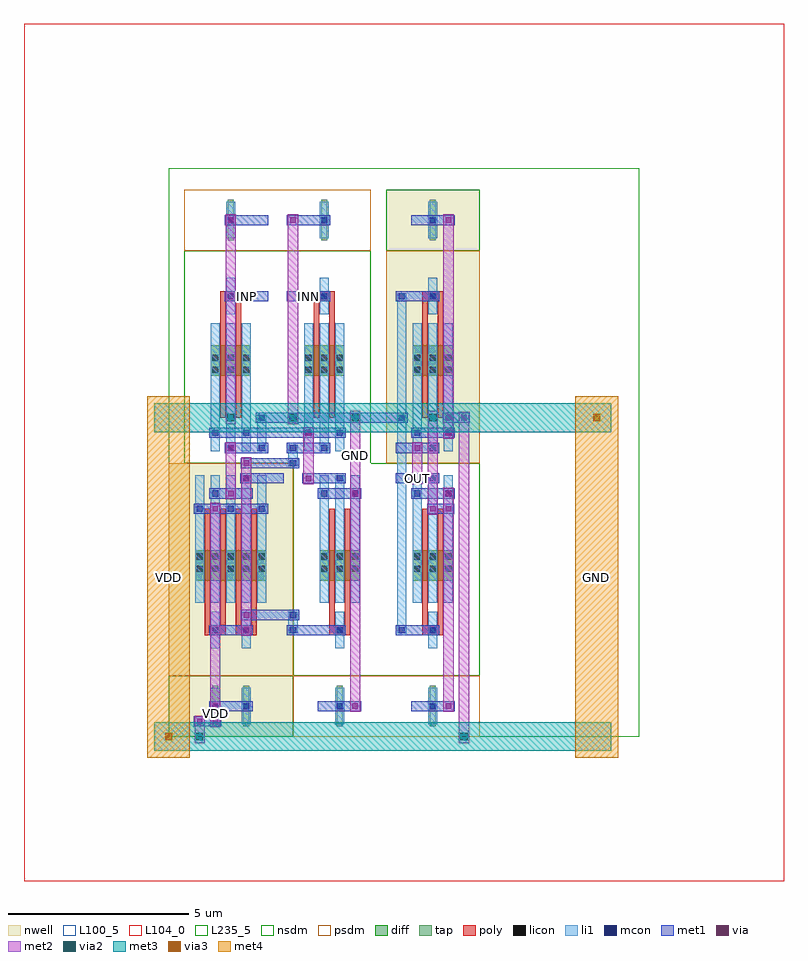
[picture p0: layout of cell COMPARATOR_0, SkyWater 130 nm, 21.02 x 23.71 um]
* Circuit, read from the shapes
.subckt COMPARATOR_0 GND INN INP OUT VDD
XM1 n1 INP n2 GND sky130_fd_pr__nfet_01v8 w=0.84 l=0.15 m=2
XM2 n3 INN n2 GND sky130_fd_pr__nfet_01v8 w=0.84 l=0.15 m=2
XM3 n2 n3 GND GND sky130_fd_pr__nfet_01v8 w=0.84 l=0.15 m=2
XM4 OUT n1 GND GND sky130_fd_pr__nfet_01v8 w=0.84 l=0.15 m=2
XM5 n1 n3 VDD VDD sky130_fd_pr__pfet_01v8 w=0.84 l=0.15 m=2
XM6 n3 n3 VDD VDD sky130_fd_pr__pfet_01v8 w=0.84 l=0.15 m=2
XM7 OUT n1 VDD VDD sky130_fd_pr__pfet_01v8 w=0.84 l=0.15 m=2
.ends

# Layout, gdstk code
from math import pi, radians
import gdstk
lib = gdstk.Library(unit=1e-6, precision=1e-09)
def R(c, l, rs):  # rectangles x0, y0, x1, y1
    for r in rs: c.add(gdstk.rectangle(r[:2], r[2:], *l))
def A(c, l, x, y, w, h, nx, ny, dx, dy):  # array of equal rectangles
    R(c, l, [(x+i*dx, y+j*dy, x+i*dx+w, y+j*dy+h) for i in range(nx) for j in range(ny)])
def P(c, l, *ps):  # polygons
    for p in ps: c.add(gdstk.Polygon(p, *l))
nwell = (64, 20)
diff = (65, 20)
tap = (65, 44)
poly = (66, 20)
licon = (66, 44)
li1 = (67, 20)
mcon = (67, 44)
met1 = (68, 20)
via = (68, 44)
met2 = (69, 20)
via2 = (69, 44)
met3 = (70, 20)
via3 = (70, 44)
met4 = (71, 20)
nsdm = (93, 44)
psdm = (94, 20)
L100_5 = (100, 5)
L104_0 = (104, 0)
L235_5 = (235, 5)

scm_pmos_73046675_x1_y1_ = lib.new_cell('SCM_PMOS_73046675_X1_Y1_1678552163')
R(scm_pmos_73046675_x1_y1_, nwell, [(0,0,3.44,7.56)])
R(scm_pmos_73046675_x1_y1_, diff, [(0.735,2.415,2.705,3.255)])
R(scm_pmos_73046675_x1_y1_, tap, [(1.205,6.16,1.375,7.28), (2.065,6.16,2.235,7.28)])
A(scm_pmos_73046675_x1_y1_, poly, 1, 1.26, 0.15, 3.36, 4, 1, 0.43, 0)
R(scm_pmos_73046675_x1_y1_, poly, [(1,4.485,1.58,4.755), (1.86,4.485,2.44,4.755)])
A(scm_pmos_73046675_x1_y1_, licon, 0.775, 2.495, 0.17, 0.17, 3, 2, 0.43, 0.34)
A(scm_pmos_73046675_x1_y1_, licon, 1.635, 2.495, 0.17, 0.17, 3, 2, 0.43, 0.34)
R(scm_pmos_73046675_x1_y1_, licon, [(1.205,4.535,1.375,4.705), (2.065,4.535,2.235,4.705), (1.205,6.635,1.375,6.805), (2.065,6.635,2.235,6.805)])
A(scm_pmos_73046675_x1_y1_, li1, 0.735, 0.335, 0.25, 3.53, 5, 1, 0.43, 0)
R(scm_pmos_73046675_x1_y1_, li1, [(1.165,4.115,1.415,5.125), (2.025,4.115,2.275,5.125), (1.165,6.215,1.415,7.225), (2.025,6.215,2.275,7.225)])
A(scm_pmos_73046675_x1_y1_, mcon, 0.775, 1.175, 0.17, 0.17, 3, 1, 0.86, 0)
R(scm_pmos_73046675_x1_y1_, mcon, [(1.205,0.335,1.375,0.505), (2.065,0.755,2.235,0.925), (1.205,4.535,1.375,4.705), (2.065,4.535,2.235,4.705), (1.205,6.635,1.375,6.805), (2.065,6.635,2.235,6.805)])
R(scm_pmos_73046675_x1_y1_, met1, [(0.26,0.28,1.46,0.56), (1.12,0.7,2.32,0.98), (0.69,1.12,2.75,1.4), (1.12,4.48,2.32,4.76), (1.12,6.58,2.32,6.86)])
R(scm_pmos_73046675_x1_y1_, via, [(1.215,0.345,1.365,0.495), (2.075,1.185,2.225,1.335), (1.215,4.545,1.365,4.695), (2.075,6.645,2.225,6.795)])
R(scm_pmos_73046675_x1_y1_, met2, [(1.15,0.26,1.43,4.78), (2.01,1.1,2.29,6.88)])
R(scm_pmos_73046675_x1_y1_, nsdm, [(0,5.88,3.44,7.56)])
R(scm_pmos_73046675_x1_y1_, psdm, [(0,0,3.44,5.88)])
R(scm_pmos_73046675_x1_y1_, L100_5, [(0,0,3.44,7.56)])

nmos_s_25628869_x1_y1_16 = lib.new_cell('NMOS_S_25628869_X1_Y1_1678552160_1678552160')
R(nmos_s_25628869_x1_y1_16, diff, [(0.735,2.415,1.845,3.255)])
R(nmos_s_25628869_x1_y1_16, tap, [(1.205,6.16,1.375,7.28)])
R(nmos_s_25628869_x1_y1_16, poly, [(1,1.26,1.15,4.62), (1.43,1.26,1.58,4.62), (1,4.485,1.58,4.755)])
A(nmos_s_25628869_x1_y1_16, licon, 0.775, 2.495, 0.17, 0.17, 3, 2, 0.43, 0.34)
R(nmos_s_25628869_x1_y1_16, licon, [(1.205,4.535,1.375,4.705), (1.205,6.635,1.375,6.805)])
A(nmos_s_25628869_x1_y1_16, li1, 0.735, 0.335, 0.25, 3.53, 3, 1, 0.43, 0)
R(nmos_s_25628869_x1_y1_16, li1, [(1.165,4.115,1.415,5.125), (1.165,6.215,1.415,7.225)])
R(nmos_s_25628869_x1_y1_16, mcon, [(1.205,0.335,1.375,0.505), (0.775,0.755,0.945,0.925), (1.635,0.755,1.805,0.925), (1.205,4.535,1.375,4.705), (1.205,6.635,1.375,6.805)])
R(nmos_s_25628869_x1_y1_16, met1, [(0.26,0.28,1.46,0.56), (0.69,0.7,1.89,0.98), (0.26,4.48,1.46,4.76), (0.69,6.58,1.89,6.86)])
R(nmos_s_25628869_x1_y1_16, via, [(1.645,0.765,1.795,0.915), (1.645,6.645,1.795,6.795)])
R(nmos_s_25628869_x1_y1_16, met2, [(1.58,0.68,1.86,6.88)])
R(nmos_s_25628869_x1_y1_16, nsdm, [(0,0,2.58,5.88)])
R(nmos_s_25628869_x1_y1_16, psdm, [(0,5.88,2.58,7.56)])
R(nmos_s_25628869_x1_y1_16, L100_5, [(0,0,2.58,7.56)])

pmos_s_36030836_x1_y1_16 = lib.new_cell('PMOS_S_36030836_X1_Y1_1678552161_1678552160')
R(pmos_s_36030836_x1_y1_16, nwell, [(0,0,2.58,7.56)])
R(pmos_s_36030836_x1_y1_16, diff, [(0.735,2.415,1.845,3.255)])
R(pmos_s_36030836_x1_y1_16, tap, [(1.205,6.16,1.375,7.28)])
R(pmos_s_36030836_x1_y1_16, poly, [(1,1.26,1.15,4.62), (1.43,1.26,1.58,4.62), (1,4.485,1.58,4.755)])
A(pmos_s_36030836_x1_y1_16, licon, 0.775, 2.495, 0.17, 0.17, 3, 2, 0.43, 0.34)
R(pmos_s_36030836_x1_y1_16, licon, [(1.205,4.535,1.375,4.705), (1.205,6.635,1.375,6.805)])
A(pmos_s_36030836_x1_y1_16, li1, 0.735, 0.335, 0.25, 3.53, 3, 1, 0.43, 0)
R(pmos_s_36030836_x1_y1_16, li1, [(1.165,4.115,1.415,5.125), (1.165,6.215,1.415,7.225)])
R(pmos_s_36030836_x1_y1_16, mcon, [(1.205,0.335,1.375,0.505), (0.775,0.755,0.945,0.925), (1.635,0.755,1.805,0.925), (1.205,4.535,1.375,4.705), (1.205,6.635,1.375,6.805)])
R(pmos_s_36030836_x1_y1_16, met1, [(0.26,0.28,1.46,0.56), (0.69,0.7,1.89,0.98), (0.26,4.48,1.46,4.76), (0.69,6.58,1.89,6.86)])
R(pmos_s_36030836_x1_y1_16, via, [(1.645,0.765,1.795,0.915), (1.645,6.645,1.795,6.795)])
R(pmos_s_36030836_x1_y1_16, met2, [(1.58,0.68,1.86,6.88)])
R(pmos_s_36030836_x1_y1_16, nsdm, [(0,5.88,2.58,7.56)])
R(pmos_s_36030836_x1_y1_16, psdm, [(0,0,2.58,5.88)])
R(pmos_s_36030836_x1_y1_16, L100_5, [(0,0,2.58,7.56)])

inv_14817437_pg0_0_0_167 = lib.new_cell('INV_14817437_PG0_0_0_1678552160')
R(inv_14817437_pg0_0_0_167, li1, [(0.305,2.855,0.555,3.025), (0.305,2.855,0.555,3.025), (0.305,2.94,0.555,12.18), (0.305,12.095,0.555,12.265), (0.305,12.095,0.555,12.265)])
R(inv_14817437_pg0_0_0_167, mcon, [(0.345,2.855,0.515,3.025), (0.345,2.855,0.515,3.025), (0.345,12.095,0.515,12.265), (0.345,12.095,0.515,12.265)])
R(inv_14817437_pg0_0_0_167, met1, [(0.26,2.8,0.6,3.08), (0.26,2.8,0.6,3.08), (0.7,7,1.02,7.28), (0.7,7,1.02,7.28), (0.7,7.84,1.02,8.12), (0.7,7.84,1.02,8.12), (0.26,12.04,0.6,12.32), (0.26,12.04,0.6,12.32)])
P(inv_14817437_pg0_0_0_167, met1, [(0,0),(0,0),(0,0),(0,0)],
  [(0,0),(0,0),(0,0),(0,0)],
  [(0,0),(0,0),(0,0),(0,0)],
  [(0,0),(0,0),(0,0),(0,0)])
R(inv_14817437_pg0_0_0_167, via, [(0.785,7.065,0.935,7.215), (0.785,7.065,0.935,7.215), (0.785,7.905,0.935,8.055), (0.785,7.905,0.935,8.055)])
R(inv_14817437_pg0_0_0_167, met2, [(0.72,6.98,1,7.3), (0.72,6.98,1,7.3), (0.72,7.14,1,7.98), (0.72,7.82,1,8.14), (0.72,7.82,1,8.14)])
P(inv_14817437_pg0_0_0_167, met2, [(0,0),(0,0),(0,0),(0,0)],
  [(0,0),(0,0),(0,0),(0,0)])
R(inv_14817437_pg0_0_0_167, L235_5, [(0,0,2.58,15.12)])
inv_14817437_pg0_0_0_167.add(gdstk.Reference(nmos_s_25628869_x1_y1_16, (0,7.56), x_reflection=True))
inv_14817437_pg0_0_0_167.add(gdstk.Reference(pmos_s_36030836_x1_y1_16, (0,7.56)))

c_nmos_s_25628869_x1_y1_16 = lib.new_cell('NMOS_S_25628869_X1_Y1_1678552162')
R(c_nmos_s_25628869_x1_y1_16, diff, [(0.735,2.415,1.845,3.255)])
R(c_nmos_s_25628869_x1_y1_16, tap, [(1.205,6.16,1.375,7.28)])
R(c_nmos_s_25628869_x1_y1_16, poly, [(1,1.26,1.15,4.62), (1.43,1.26,1.58,4.62), (1,4.485,1.58,4.755)])
A(c_nmos_s_25628869_x1_y1_16, licon, 0.775, 2.495, 0.17, 0.17, 3, 2, 0.43, 0.34)
R(c_nmos_s_25628869_x1_y1_16, licon, [(1.205,4.535,1.375,4.705), (1.205,6.635,1.375,6.805)])
A(c_nmos_s_25628869_x1_y1_16, li1, 0.735, 0.335, 0.25, 3.53, 3, 1, 0.43, 0)
R(c_nmos_s_25628869_x1_y1_16, li1, [(1.165,4.115,1.415,5.125), (1.165,6.215,1.415,7.225)])
R(c_nmos_s_25628869_x1_y1_16, mcon, [(1.205,0.335,1.375,0.505), (0.775,0.755,0.945,0.925), (1.635,0.755,1.805,0.925), (1.205,4.535,1.375,4.705), (1.205,6.635,1.375,6.805)])
R(c_nmos_s_25628869_x1_y1_16, met1, [(0.26,0.28,1.46,0.56), (0.69,0.7,1.89,0.98), (0.26,4.48,1.46,4.76), (0.69,6.58,1.89,6.86)])
R(c_nmos_s_25628869_x1_y1_16, via, [(1.645,0.765,1.795,0.915), (1.645,6.645,1.795,6.795)])
R(c_nmos_s_25628869_x1_y1_16, met2, [(1.58,0.68,1.86,6.88)])
R(c_nmos_s_25628869_x1_y1_16, nsdm, [(0,0,2.58,5.88)])
R(c_nmos_s_25628869_x1_y1_16, psdm, [(0,5.88,2.58,7.56)])
R(c_nmos_s_25628869_x1_y1_16, L100_5, [(0,0,2.58,7.56)])

nmos_4t_90354340_x1_y1_1 = lib.new_cell('NMOS_4T_90354340_X1_Y1_1678552161')
R(nmos_4t_90354340_x1_y1_1, diff, [(0.735,2.415,1.845,3.255)])
R(nmos_4t_90354340_x1_y1_1, tap, [(1.205,6.16,1.375,7.28)])
R(nmos_4t_90354340_x1_y1_1, poly, [(1,1.26,1.15,4.62), (1.43,1.26,1.58,4.62), (1,4.485,1.58,4.755)])
A(nmos_4t_90354340_x1_y1_1, licon, 0.775, 2.495, 0.17, 0.17, 3, 2, 0.43, 0.34)
R(nmos_4t_90354340_x1_y1_1, licon, [(1.205,4.535,1.375,4.705), (1.205,6.635,1.375,6.805)])
A(nmos_4t_90354340_x1_y1_1, li1, 0.735, 0.335, 0.25, 3.53, 3, 1, 0.43, 0)
R(nmos_4t_90354340_x1_y1_1, li1, [(1.165,4.115,1.415,5.125), (1.165,6.215,1.415,7.225)])
R(nmos_4t_90354340_x1_y1_1, mcon, [(1.205,0.335,1.375,0.505), (0.775,0.755,0.945,0.925), (1.635,0.755,1.805,0.925), (1.205,4.535,1.375,4.705), (1.205,6.635,1.375,6.805)])
R(nmos_4t_90354340_x1_y1_1, met1, [(0.26,0.28,1.46,0.56), (0.69,0.7,1.89,0.98), (0.26,4.48,1.46,4.76), (0.26,6.58,1.46,6.86)])
R(nmos_4t_90354340_x1_y1_1, nsdm, [(0,0,2.58,5.88)])
R(nmos_4t_90354340_x1_y1_1, psdm, [(0,5.88,2.58,7.56)])
R(nmos_4t_90354340_x1_y1_1, L100_5, [(0,0,2.58,7.56)])

comparator_0 = lib.new_cell('COMPARATOR_0')
R(comparator_0, li1, [(3.315,2.855,3.565,3.025), (3.315,2.855,3.565,3.025), (3.315,2.855,3.565,3.025), (3.315,2.855,3.565,3.025), (3.315,2.94,3.565,3.36), (3.315,3.275,3.565,3.445), (3.315,3.275,3.565,3.445), (3.315,3.275,3.565,3.445), (3.315,3.275,3.565,3.445), (3.315,7.475,3.565,7.645), (3.315,7.475,3.565,7.645), (3.315,7.56,3.565,7.98), (2.455,7.895,2.705,8.065), (2.455,7.895,2.705,8.065), (3.315,7.895,3.565,8.065), (3.315,7.895,3.565,8.065), (2.455,7.98,2.705,8.82), (2.455,8.735,2.705,8.905), (2.455,8.735,2.705,8.905), (6.325,8.735,6.575,8.905), (6.325,8.735,6.575,8.905)])
P(comparator_0, li1, [(0,0),(0,0),(0,0),(0,0)])
R(comparator_0, mcon, [(3.355,2.855,3.525,3.025), (3.355,2.855,3.525,3.025), (3.355,2.855,3.525,3.025), (3.355,2.855,3.525,3.025), (3.355,3.275,3.525,3.445), (3.355,3.275,3.525,3.445), (3.355,3.275,3.525,3.445), (3.355,3.275,3.525,3.445), (3.355,7.475,3.525,7.645), (3.355,7.475,3.525,7.645), (2.495,7.895,2.665,8.065), (2.495,7.895,2.665,8.065), (3.355,7.895,3.525,8.065), (3.355,7.895,3.525,8.065), (2.495,8.735,2.665,8.905), (2.495,8.735,2.665,8.905), (6.365,8.735,6.535,8.905), (6.365,8.735,6.535,8.905)])
R(comparator_0, met1, [(0.7,0.28,1.02,0.56), (0.7,0.28,1.02,0.56), (0.7,0.28,1.02,0.56), (0.86,0.28,1.29,0.56), (1.13,0.28,1.45,0.56), (1.13,0.28,1.45,0.56), (1.13,0.28,1.45,0.56), (3.27,2.8,3.61,3.08), (3.27,2.8,3.61,3.08), (3.27,2.8,3.61,3.08), (3.27,2.8,3.61,3.08), (3.44,2.8,3.87,3.08), (1.99,3.22,2.31,3.5), (1.99,3.22,2.31,3.5), (1.99,3.22,2.31,3.5), (1.99,3.22,2.31,3.5), (2.15,3.22,3.44,3.5), (3.27,3.22,3.61,3.5), (3.27,3.22,3.61,3.5), (3.27,3.22,3.61,3.5), (3.27,3.22,3.61,3.5), (7.15,6.16,7.47,6.44), (7.15,6.16,7.47,6.44), (7.31,6.16,7.74,6.44), (7.58,6.16,7.9,6.44), (7.58,6.16,7.9,6.44), (1.56,6.58,1.88,6.86), (1.56,6.58,1.88,6.86), (1.56,6.58,1.88,6.86), (1.56,6.58,1.88,6.86), (3.71,7,4.03,7.28), (3.71,7,4.03,7.28), (1.99,7.42,2.31,7.7), (1.99,7.42,2.31,7.7), (2.15,7.42,3.44,7.7), (3.27,7.42,3.61,7.7), (3.27,7.42,3.61,7.7), (1.56,7.84,1.88,8.12), (1.56,7.84,1.88,8.12), (1.56,7.84,1.88,8.12), (1.56,7.84,1.88,8.12), (2.41,7.84,2.75,8.12), (2.41,7.84,2.75,8.12), (3.27,7.84,3.61,8.12), (3.27,7.84,3.61,8.12), (2.15,8.26,3.87,8.54), (3.71,8.26,4.03,8.54), (3.71,8.26,4.03,8.54), (2.41,8.68,2.75,8.96), (2.41,8.68,2.75,8.96), (2.58,8.68,6.45,8.96), (6.28,8.68,6.62,8.96), (6.28,8.68,6.62,8.96), (7.58,8.68,7.9,8.96), (7.58,8.68,7.9,8.96), (7.74,8.68,8.17,8.96), (8.01,8.68,8.33,8.96), (8.01,8.68,8.33,8.96), (1.56,14.14,1.88,14.42), (1.56,14.14,1.88,14.42), (1.56,14.14,1.88,14.42), (1.56,14.14,1.88,14.42), (3.28,14.14,3.6,14.42), (3.28,14.14,3.6,14.42), (3.28,14.14,3.6,14.42)])
P(comparator_0, met1, [(0,0),(0,0),(0,0),(0,0)],
  [(0,0),(0,0),(0,0),(0,0)],
  [(0,0),(0,0),(0,0),(0,0)],
  [(0,0),(0,0),(0,0),(0,0)],
  [(0,0),(0,0),(0,0),(0,0)],
  [(0,0),(0,0),(0,0),(0,0)],
  [(0,0),(0,0),(0,0),(0,0)],
  [(0,0),(0,0),(0,0),(0,0)],
  [(0,0),(0,0),(0,0),(0,0)],
  [(0,0),(0,0),(0,0),(0,0)],
  [(0,0),(0,0),(0,0),(0,0)],
  [(0,0),(0,0),(0,0),(0,0)],
  [(0,0),(0,0),(0,0),(0,0)],
  [(0,0),(0,0),(0,0),(0,0)],
  [(0,0),(0,0),(0,0),(0,0)],
  [(0,0),(0,0),(0,0),(0,0)],
  [(0,0),(0,0),(0,0),(0,0)],
  [(0,0),(0,0),(0,0),(0,0)],
  [(0,0),(0,0),(0,0),(0,0)],
  [(0,0),(0,0),(0,0),(0,0)],
  [(0,0),(0,0),(0,0),(0,0)],
  [(0,0),(0,0),(0,0),(0,0)])
R(comparator_0, via, [(0.785,0.345,0.935,0.495), (0.785,0.345,0.935,0.495), (0.785,0.345,0.935,0.495), (1.215,0.345,1.365,0.495), (1.215,0.345,1.365,0.495), (1.215,0.345,1.365,0.495), (2.075,3.285,2.225,3.435), (2.075,3.285,2.225,3.435), (2.075,3.285,2.225,3.435), (2.075,3.285,2.225,3.435), (7.235,6.225,7.385,6.375), (7.235,6.225,7.385,6.375), (7.665,6.225,7.815,6.375), (7.665,6.225,7.815,6.375), (1.645,6.645,1.795,6.795), (1.645,6.645,1.795,6.795), (1.645,6.645,1.795,6.795), (1.645,6.645,1.795,6.795), (3.795,7.065,3.945,7.215), (3.795,7.065,3.945,7.215), (2.075,7.485,2.225,7.635), (2.075,7.485,2.225,7.635), (1.645,7.905,1.795,8.055), (1.645,7.905,1.795,8.055), (1.645,7.905,1.795,8.055), (1.645,7.905,1.795,8.055), (3.795,8.325,3.945,8.475), (3.795,8.325,3.945,8.475), (7.665,8.745,7.815,8.895), (7.665,8.745,7.815,8.895), (8.095,8.745,8.245,8.895), (8.095,8.745,8.245,8.895), (1.645,14.205,1.795,14.355), (1.645,14.205,1.795,14.355), (1.645,14.205,1.795,14.355), (1.645,14.205,1.795,14.355), (3.365,14.205,3.515,14.355), (3.365,14.205,3.515,14.355), (3.365,14.205,3.515,14.355)])
R(comparator_0, met2, [(0.72,-0.185,1,0.185), (0.72,-0.185,1,0.185), (0.72,-0.185,1,0.185), (8.03,-0.185,8.31,0.185), (8.03,-0.185,8.31,0.185), (0.72,0,1,0.42), (8.03,0,8.31,8.82), (0.72,0.26,1,0.58), (0.72,0.26,1,0.58), (0.72,0.26,1,0.58), (1.15,0.26,1.43,0.58), (1.15,0.26,1.43,0.58), (1.15,0.26,1.43,0.58), (1.15,0.42,1.43,0.84), (2.01,3.2,2.29,3.52), (2.01,3.2,2.29,3.52), (2.01,3.2,2.29,3.52), (2.01,3.2,2.29,3.52), (7.17,6.14,7.45,6.46), (7.17,6.14,7.45,6.46), (7.6,6.14,7.88,6.46), (7.6,6.14,7.88,6.46), (7.17,6.3,7.45,8.82), (1.58,6.56,1.86,6.88), (1.58,6.56,1.86,6.88), (1.58,6.56,1.86,6.88), (1.58,6.56,1.86,6.88), (1.58,6.72,1.86,7.98), (5.02,6.72,5.3,8.82), (3.73,6.98,4.01,7.3), (3.73,6.98,4.01,7.3), (2.01,7.14,2.29,7.56), (3.73,7.14,4.01,8.4), (2.01,7.4,2.29,7.72), (2.01,7.4,2.29,7.72), (1.58,7.82,1.86,8.14), (1.58,7.82,1.86,8.14), (1.58,7.82,1.86,8.14), (1.58,7.82,1.86,8.14), (3.73,8.24,4.01,8.56), (3.73,8.24,4.01,8.56), (1.58,8.635,1.86,9.005), (1.58,8.635,1.86,9.005), (1.58,8.635,1.86,9.005), (1.58,8.635,1.86,9.005), (3.3,8.635,3.58,9.005), (3.3,8.635,3.58,9.005), (3.3,8.635,3.58,9.005), (5.02,8.635,5.3,9.005), (5.02,8.635,5.3,9.005), (5.02,8.635,5.3,9.005), (5.02,8.635,5.3,9.005), (5.02,8.635,5.3,9.005), (7.17,8.635,7.45,9.005), (7.17,8.635,7.45,9.005), (7.6,8.66,7.88,8.98), (7.6,8.66,7.88,8.98), (8.03,8.66,8.31,8.98), (8.03,8.66,8.31,8.98), (1.58,8.82,1.86,14.28), (3.3,8.82,3.58,14.28), (1.58,14.12,1.86,14.44), (1.58,14.12,1.86,14.44), (1.58,14.12,1.86,14.44), (1.58,14.12,1.86,14.44), (3.3,14.12,3.58,14.44), (3.3,14.12,3.58,14.44), (3.3,14.12,3.58,14.44)])
P(comparator_0, met2, [(0,0),(0,0),(0,0),(0,0)],
  [(0,0),(0,0),(0,0),(0,0)],
  [(0,0),(0,0),(0,0),(0,0)],
  [(0,0),(0,0),(0,0),(0,0)])
R(comparator_0, via2, [(0.76,-0.1,0.96,0.1), (0.76,-0.1,0.96,0.1), (0.76,-0.1,0.96,0.1), (8.07,-0.1,8.27,0.1), (8.07,-0.1,8.27,0.1), (1.62,8.72,1.82,8.92), (1.62,8.72,1.82,8.92), (1.62,8.72,1.82,8.92), (1.62,8.72,1.82,8.92), (3.34,8.72,3.54,8.92), (3.34,8.72,3.54,8.92), (3.34,8.72,3.54,8.92), (5.06,8.72,5.26,8.92), (5.06,8.72,5.26,8.92), (5.06,8.72,5.26,8.92), (5.06,8.72,5.26,8.92), (5.06,8.72,5.26,8.92), (7.21,8.72,7.41,8.92), (7.21,8.72,7.41,8.92)])
A(comparator_0, met3, -0.4, -0.4, 4.24, 0.8, 3, 2, 3.44, 8.82)
R(comparator_0, met3, [(-0.165,-0.4,0.165,0.4), (0.695,-0.4,1.025,0.4), (0.695,-0.4,1.025,0.4), (0.695,-0.4,1.025,0.4), (8.005,-0.4,8.335,0.4), (8.005,-0.4,8.335,0.4), (9.92,-0.4,12.24,0.4), (1.555,8.42,1.885,9.22), (1.555,8.42,1.885,9.22), (1.555,8.42,1.885,9.22), (1.555,8.42,1.885,9.22), (3.275,8.42,3.605,9.22), (3.275,8.42,3.605,9.22), (3.275,8.42,3.605,9.22), (4.995,8.42,5.325,9.22), (4.995,8.42,5.325,9.22), (4.995,8.42,5.325,9.22), (4.995,8.42,5.325,9.22), (4.995,8.42,5.325,9.22), (7.145,8.42,7.475,9.22), (7.145,8.42,7.475,9.22), (9.92,8.42,12.24,9.22), (11.675,8.42,12.005,9.22)])
R(comparator_0, via3, [(-0.1,-0.1,0.1,0.1), (11.74,8.72,11.94,8.92)])
R(comparator_0, met4, [(-0.59,-0.59,0.59,9.41), (11.25,-0.59,12.43,9.41), (-0.59,-0.165,0.59,0.165), (11.25,8.655,12.43,8.985)])
R(comparator_0, L104_0, [(-4,-4,17.02,19.71)])
R(comparator_0, L235_5, [(0,0,13.02,15.71)])
comparator_0.add(gdstk.Reference(scm_pmos_73046675_x1_y1_, (3.44,7.56), rotation=pi))
comparator_0.add(gdstk.Reference(inv_14817437_pg0_0_0_167, (6.02,0)))
comparator_0.add(gdstk.Reference(c_nmos_s_25628869_x1_y1_16, (3.44,7.56), x_reflection=True))
comparator_0.add(gdstk.Reference(nmos_4t_90354340_x1_y1_1, (3.01,7.56), rotation=pi, x_reflection=True))
comparator_0.add(gdstk.Reference(nmos_4t_90354340_x1_y1_1, (3.01,7.56)))
comparator_0.add(gdstk.Label('OUT', (6.88,7.14), layer=68, texttype=5))
comparator_0.add(gdstk.Label('INP', (2.15,12.18), layer=68, texttype=5))
comparator_0.add(gdstk.Label('INN', (3.87,12.18), layer=68, texttype=5))
comparator_0.add(gdstk.Label('GND', (5.16,7.77), layer=69, texttype=5))
comparator_0.add(gdstk.Label('GND', (11.84,4.41), layer=71, texttype=5))
comparator_0.add(gdstk.Label('GND', (11.84,4.41), layer=71, texttype=5))
comparator_0.add(gdstk.Label('GND', (11.84,4.41), layer=71, texttype=5))
comparator_0.add(gdstk.Label('GND', (11.84,4.41), layer=71, texttype=5))
comparator_0.add(gdstk.Label('GND', (11.84,4.41), layer=71, texttype=5))
comparator_0.add(gdstk.Label('GND', (11.84,4.41), layer=71, texttype=5))
comparator_0.add(gdstk.Label('GND', (11.84,4.41), layer=71, texttype=5))
comparator_0.add(gdstk.Label('GND', (11.84,4.41), layer=71, texttype=5))
comparator_0.add(gdstk.Label('GND', (11.84,4.41), layer=71, texttype=5))
comparator_0.add(gdstk.Label('GND', (11.84,4.41), layer=71, texttype=5))
comparator_0.add(gdstk.Label('GND', (11.84,4.41), layer=71, texttype=5))
comparator_0.add(gdstk.Label('GND', (11.84,4.41), layer=71, texttype=5))
comparator_0.add(gdstk.Label('VDD', (1.29,0.63), layer=69, texttype=5))
comparator_0.add(gdstk.Label('VDD', (0,4.41), layer=71, texttype=5))
comparator_0.add(gdstk.Label('VDD', (0,4.41), layer=71, texttype=5))
comparator_0.add(gdstk.Label('VDD', (0,4.41), layer=71, texttype=5))
comparator_0.add(gdstk.Label('VDD', (0,4.41), layer=71, texttype=5))
comparator_0.add(gdstk.Label('VDD', (0,4.41), layer=71, texttype=5))
comparator_0.add(gdstk.Label('VDD', (0,4.41), layer=71, texttype=5))
comparator_0.add(gdstk.Label('VDD', (0,4.41), layer=71, texttype=5))
comparator_0.add(gdstk.Label('VDD', (0,4.41), layer=71, texttype=5))

lib.write_gds('COMPARATOR_0.gds')
